One B-rep face of a CAD part: STEP entity #333.
In plain terms, the planar face has unit normal (0, -1, 0).
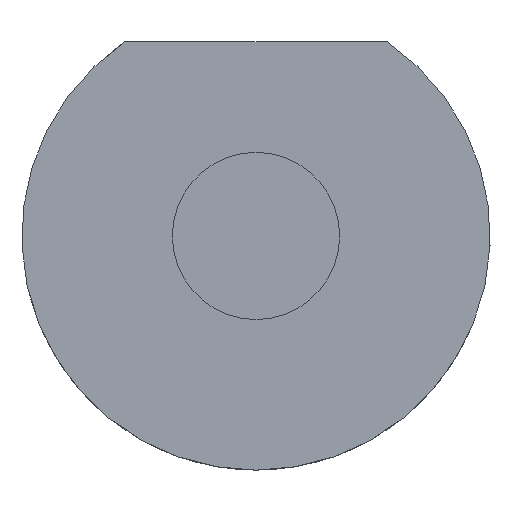
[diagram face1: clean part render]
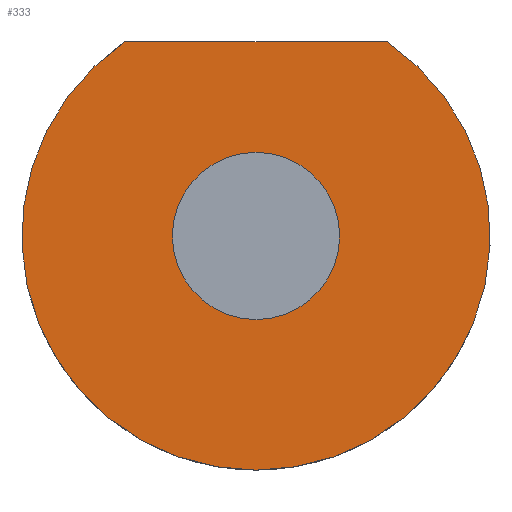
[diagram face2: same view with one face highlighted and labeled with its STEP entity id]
Its self-contained STEP definition (entity closure, numbers rounded to 3 decimals):
#42 = VERTEX_POINT('',#43);
#43 = CARTESIAN_POINT('',(1.96,-35.5,2.9));
#50 = CYLINDRICAL_SURFACE('',#51,3.5);
#51 = AXIS2_PLACEMENT_3D('',#52,#53,#54);
#52 = CARTESIAN_POINT('',(0.,-9.22,0.));
#53 = DIRECTION('',(0.,-1.,0.));
#54 = DIRECTION('',(1.,0.,0.));
#61 = PLANE('',#62);
#62 = AXIS2_PLACEMENT_3D('',#63,#64,#65);
#63 = CARTESIAN_POINT('',(-5.,-36.5,2.9));
#64 = DIRECTION('',(0.,0.,1.));
#65 = DIRECTION('',(1.,0.,-0.));
#72 = EDGE_CURVE('',#42,#73,#75,.T.);
#73 = VERTEX_POINT('',#74);
#74 = CARTESIAN_POINT('',(-1.96,-35.5,2.9));
#75 = SURFACE_CURVE('',#76,(#81,#88),.PCURVE_S1.);
#76 = CIRCLE('',#77,3.5);
#77 = AXIS2_PLACEMENT_3D('',#78,#79,#80);
#78 = CARTESIAN_POINT('',(0.,-35.5,0.));
#79 = DIRECTION('',(0.,1.,0.));
#80 = DIRECTION('',(0.56,-0.,0.829));
#81 = PCURVE('',#50,#82);
#82 = DEFINITIONAL_REPRESENTATION('',(#83),#87);
#83 = LINE('',#84,#85);
#84 = CARTESIAN_POINT('',(7.26,26.28));
#85 = VECTOR('',#86,1.);
#86 = DIRECTION('',(-1.,-0.));
#87 = ( GEOMETRIC_REPRESENTATION_CONTEXT(2) 
PARAMETRIC_REPRESENTATION_CONTEXT() REPRESENTATION_CONTEXT('2D SPACE',''
  ) );
#88 = PCURVE('',#89,#94);
#89 = PLANE('',#90);
#90 = AXIS2_PLACEMENT_3D('',#91,#92,#93);
#91 = CARTESIAN_POINT('',(0.,-35.5,0.));
#92 = DIRECTION('',(0.,-1.,0.));
#93 = DIRECTION('',(1.,0.,0.));
#94 = DEFINITIONAL_REPRESENTATION('',(#95),#103);
#95 = ( BOUNDED_CURVE() B_SPLINE_CURVE(2,(#96,#97,#98,#99,#100,#101,#102
),.UNSPECIFIED.,.T.,.F.) B_SPLINE_CURVE_WITH_KNOTS((1,2,2,2,2,1),(
    -2.094,0.,2.094,4.189,6.283,
8.378),.UNSPECIFIED.) CURVE() GEOMETRIC_REPRESENTATION_ITEM() 
RATIONAL_B_SPLINE_CURVE((1.,0.5,1.,0.5,1.,0.5,1.)) REPRESENTATION_ITEM(
  '') );
#96 = CARTESIAN_POINT('',(1.96,2.9));
#97 = CARTESIAN_POINT('',(6.983,-0.494));
#98 = CARTESIAN_POINT('',(1.532,-3.147));
#99 = CARTESIAN_POINT('',(-3.919,-5.8));
#100 = CARTESIAN_POINT('',(-3.491,0.247));
#101 = CARTESIAN_POINT('',(-3.063,6.294));
#102 = CARTESIAN_POINT('',(1.96,2.9));
#103 = ( GEOMETRIC_REPRESENTATION_CONTEXT(2) 
PARAMETRIC_REPRESENTATION_CONTEXT() REPRESENTATION_CONTEXT('2D SPACE',''
  ) );
#184 = EDGE_CURVE('',#42,#73,#185,.T.);
#185 = SURFACE_CURVE('',#186,(#190,#196),.PCURVE_S1.);
#186 = LINE('',#187,#188);
#187 = CARTESIAN_POINT('',(-2.5,-35.5,2.9));
#188 = VECTOR('',#189,1.);
#189 = DIRECTION('',(-1.,0.,0.));
#190 = PCURVE('',#61,#191);
#191 = DEFINITIONAL_REPRESENTATION('',(#192),#195);
#192 = B_SPLINE_CURVE_WITH_KNOTS('',1,(#193,#194),.UNSPECIFIED.,.F.,.F.,
  (2,2),(-6.,1.),.PIECEWISE_BEZIER_KNOTS.);
#193 = CARTESIAN_POINT('',(8.5,1.));
#194 = CARTESIAN_POINT('',(1.5,1.));
#195 = ( GEOMETRIC_REPRESENTATION_CONTEXT(2) 
PARAMETRIC_REPRESENTATION_CONTEXT() REPRESENTATION_CONTEXT('2D SPACE',''
  ) );
#196 = PCURVE('',#89,#197);
#197 = DEFINITIONAL_REPRESENTATION('',(#198),#201);
#198 = B_SPLINE_CURVE_WITH_KNOTS('',1,(#199,#200),.UNSPECIFIED.,.F.,.F.,
  (2,2),(-6.,1.),.PIECEWISE_BEZIER_KNOTS.);
#199 = CARTESIAN_POINT('',(3.5,2.9));
#200 = CARTESIAN_POINT('',(-3.5,2.9));
#201 = ( GEOMETRIC_REPRESENTATION_CONTEXT(2) 
PARAMETRIC_REPRESENTATION_CONTEXT() REPRESENTATION_CONTEXT('2D SPACE',''
  ) );
#333 = ADVANCED_FACE('',(#334,#338),#89,.T.);
#334 = FACE_BOUND('',#335,.T.);
#335 = EDGE_LOOP('',(#336,#337));
#336 = ORIENTED_EDGE('',*,*,#184,.T.);
#337 = ORIENTED_EDGE('',*,*,#72,.F.);
#338 = FACE_BOUND('',#339,.T.);
#339 = EDGE_LOOP('',(#340));
#340 = ORIENTED_EDGE('',*,*,#341,.F.);
#341 = EDGE_CURVE('',#342,#342,#344,.T.);
#342 = VERTEX_POINT('',#343);
#343 = CARTESIAN_POINT('',(1.25,-35.5,0.));
#344 = SURFACE_CURVE('',#345,(#350,#357),.PCURVE_S1.);
#345 = CIRCLE('',#346,1.25);
#346 = AXIS2_PLACEMENT_3D('',#347,#348,#349);
#347 = CARTESIAN_POINT('',(0.,-35.5,0.));
#348 = DIRECTION('',(0.,-1.,0.));
#349 = DIRECTION('',(1.,0.,0.));
#350 = PCURVE('',#89,#351);
#351 = DEFINITIONAL_REPRESENTATION('',(#352),#356);
#352 = CIRCLE('',#353,1.25);
#353 = AXIS2_PLACEMENT_2D('',#354,#355);
#354 = CARTESIAN_POINT('',(0.,0.));
#355 = DIRECTION('',(1.,0.));
#356 = ( GEOMETRIC_REPRESENTATION_CONTEXT(2) 
PARAMETRIC_REPRESENTATION_CONTEXT() REPRESENTATION_CONTEXT('2D SPACE',''
  ) );
#357 = PCURVE('',#358,#363);
#358 = CYLINDRICAL_SURFACE('',#359,1.25);
#359 = AXIS2_PLACEMENT_3D('',#360,#361,#362);
#360 = CARTESIAN_POINT('',(0.,-28.5,0.));
#361 = DIRECTION('',(0.,-1.,0.));
#362 = DIRECTION('',(1.,0.,0.));
#363 = DEFINITIONAL_REPRESENTATION('',(#364),#368);
#364 = LINE('',#365,#366);
#365 = CARTESIAN_POINT('',(0.,7.));
#366 = VECTOR('',#367,1.);
#367 = DIRECTION('',(1.,0.));
#368 = ( GEOMETRIC_REPRESENTATION_CONTEXT(2) 
PARAMETRIC_REPRESENTATION_CONTEXT() REPRESENTATION_CONTEXT('2D SPACE',''
  ) );
